VERSION 5.7 ;
  NOWIREEXTENSIONATPIN ON ;
  DIVIDERCHAR "/" ;
  BUSBITCHARS "[]" ;
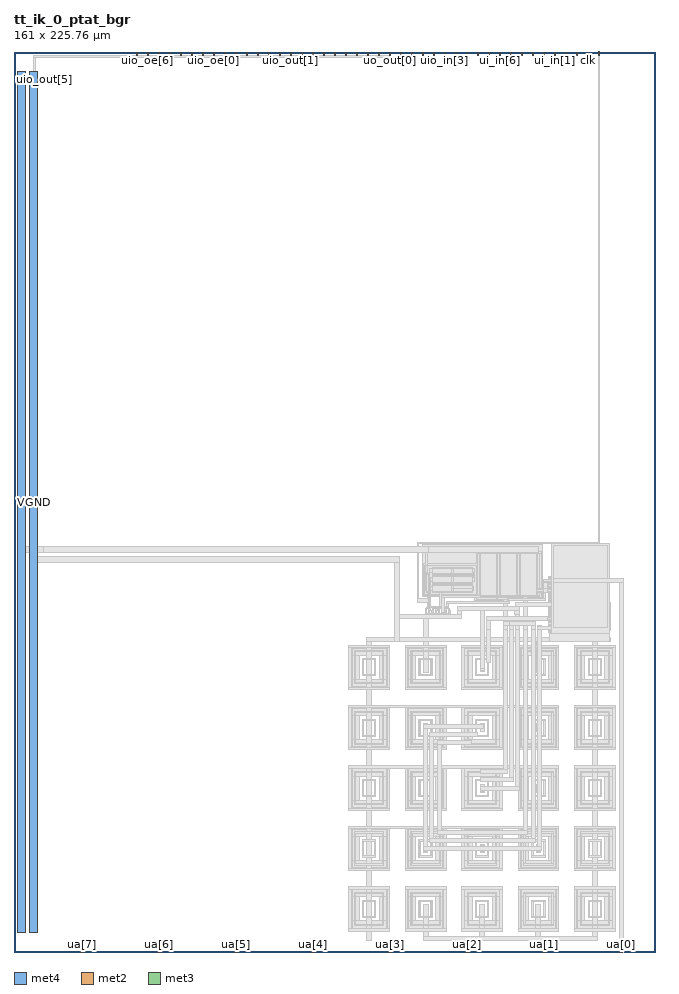
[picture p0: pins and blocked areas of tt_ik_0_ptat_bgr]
MACRO tt_ik_0_ptat_bgr
  CLASS BLOCK ;
  FOREIGN tt_ik_0_ptat_bgr ;
  ORIGIN 0.000 0.000 ;
  SIZE 161.000 BY 225.760 ;
  PIN clk
    DIRECTION INPUT ;
    USE SIGNAL ;
    PORT
      LAYER met4 ;
        RECT 143.830 224.760 144.130 225.760 ;
    END
  END clk
  PIN ena
    DIRECTION INPUT ;
    USE SIGNAL ;
    ANTENNAGATEAREA 1.000000 ;
    PORT
      LAYER met2 ;
        RECT 146.500 225.760 146.950 225.800 ;
      LAYER met3 ;
        RECT 146.500 225.760 146.950 225.800 ;
      LAYER met4 ;
        RECT 146.500 225.760 146.950 225.800 ;
        RECT 146.590 224.760 146.890 225.760 ;
    END
  END ena
  PIN rst_n
    DIRECTION INPUT ;
    USE SIGNAL ;
    PORT
      LAYER met4 ;
        RECT 141.070 224.760 141.370 225.760 ;
    END
  END rst_n
  PIN ua[0]
    DIRECTION INOUT ;
    USE SIGNAL ;
    PORT
      LAYER met4 ;
        RECT 151.810 0.000 152.710 1.000 ;
    END
  END ua[0]
  PIN ua[1]
    DIRECTION INOUT ;
    USE SIGNAL ;
    PORT
      LAYER met4 ;
        RECT 132.490 0.000 133.390 1.000 ;
    END
  END ua[1]
  PIN ua[2]
    DIRECTION INOUT ;
    USE SIGNAL ;
    PORT
      LAYER met4 ;
        RECT 113.170 0.000 114.070 1.000 ;
    END
  END ua[2]
  PIN ua[3]
    DIRECTION INOUT ;
    USE SIGNAL ;
    PORT
      LAYER met4 ;
        RECT 93.850 0.000 94.750 1.000 ;
    END
  END ua[3]
  PIN ua[4]
    DIRECTION INOUT ;
    USE SIGNAL ;
    PORT
      LAYER met4 ;
        RECT 74.530 0.000 75.430 1.000 ;
    END
  END ua[4]
  PIN ua[5]
    DIRECTION INOUT ;
    USE SIGNAL ;
    PORT
      LAYER met4 ;
        RECT 55.210 0.000 56.110 1.000 ;
    END
  END ua[5]
  PIN ua[6]
    DIRECTION INOUT ;
    USE SIGNAL ;
    PORT
      LAYER met4 ;
        RECT 35.890 0.000 36.790 1.000 ;
    END
  END ua[6]
  PIN ua[7]
    DIRECTION INOUT ;
    USE SIGNAL ;
    PORT
      LAYER met4 ;
        RECT 16.570 0.000 17.470 1.000 ;
    END
  END ua[7]
  PIN ui_in[0]
    DIRECTION INPUT ;
    USE SIGNAL ;
    PORT
      LAYER met4 ;
        RECT 138.310 224.760 138.610 225.760 ;
    END
  END ui_in[0]
  PIN ui_in[1]
    DIRECTION INPUT ;
    USE SIGNAL ;
    PORT
      LAYER met4 ;
        RECT 135.550 224.760 135.850 225.760 ;
    END
  END ui_in[1]
  PIN ui_in[2]
    DIRECTION INPUT ;
    USE SIGNAL ;
    PORT
      LAYER met4 ;
        RECT 132.790 224.760 133.090 225.760 ;
    END
  END ui_in[2]
  PIN ui_in[3]
    DIRECTION INPUT ;
    USE SIGNAL ;
    PORT
      LAYER met4 ;
        RECT 130.030 224.760 130.330 225.760 ;
    END
  END ui_in[3]
  PIN ui_in[4]
    DIRECTION INPUT ;
    USE SIGNAL ;
    PORT
      LAYER met4 ;
        RECT 127.270 224.760 127.570 225.760 ;
    END
  END ui_in[4]
  PIN ui_in[5]
    DIRECTION INPUT ;
    USE SIGNAL ;
    PORT
      LAYER met4 ;
        RECT 124.510 224.760 124.810 225.760 ;
    END
  END ui_in[5]
  PIN ui_in[6]
    DIRECTION INPUT ;
    USE SIGNAL ;
    PORT
      LAYER met4 ;
        RECT 121.750 224.760 122.050 225.760 ;
    END
  END ui_in[6]
  PIN ui_in[7]
    DIRECTION INPUT ;
    USE SIGNAL ;
    PORT
      LAYER met4 ;
        RECT 118.990 224.760 119.290 225.760 ;
    END
  END ui_in[7]
  PIN uio_in[0]
    DIRECTION INPUT ;
    USE SIGNAL ;
    PORT
      LAYER met4 ;
        RECT 116.230 224.760 116.530 225.760 ;
    END
  END uio_in[0]
  PIN uio_in[1]
    DIRECTION INPUT ;
    USE SIGNAL ;
    PORT
      LAYER met4 ;
        RECT 113.470 224.760 113.770 225.760 ;
    END
  END uio_in[1]
  PIN uio_in[2]
    DIRECTION INPUT ;
    USE SIGNAL ;
    PORT
      LAYER met4 ;
        RECT 110.710 224.760 111.010 225.760 ;
    END
  END uio_in[2]
  PIN uio_in[3]
    DIRECTION INPUT ;
    USE SIGNAL ;
    PORT
      LAYER met4 ;
        RECT 107.950 224.760 108.250 225.760 ;
    END
  END uio_in[3]
  PIN uio_in[4]
    DIRECTION INPUT ;
    USE SIGNAL ;
    PORT
      LAYER met4 ;
        RECT 105.190 224.760 105.490 225.760 ;
    END
  END uio_in[4]
  PIN uio_in[5]
    DIRECTION INPUT ;
    USE SIGNAL ;
    PORT
      LAYER met4 ;
        RECT 102.430 224.760 102.730 225.760 ;
    END
  END uio_in[5]
  PIN uio_in[6]
    DIRECTION INPUT ;
    USE SIGNAL ;
    PORT
      LAYER met4 ;
        RECT 99.670 224.760 99.970 225.760 ;
    END
  END uio_in[6]
  PIN uio_in[7]
    DIRECTION INPUT ;
    USE SIGNAL ;
    PORT
      LAYER met4 ;
        RECT 96.910 224.760 97.210 225.760 ;
    END
  END uio_in[7]
  PIN uio_oe[0]
    DIRECTION OUTPUT ;
    USE SIGNAL ;
    ANTENNAGATEAREA 453.306000 ;
    ANTENNADIFFAREA 915.978760 ;
    PORT
      LAYER met4 ;
        RECT 49.990 224.760 50.290 225.760 ;
    END
  END uio_oe[0]
  PIN uio_oe[1]
    DIRECTION OUTPUT ;
    USE SIGNAL ;
    ANTENNAGATEAREA 453.306000 ;
    ANTENNADIFFAREA 915.978760 ;
    PORT
      LAYER met4 ;
        RECT 47.230 224.760 47.530 225.760 ;
    END
  END uio_oe[1]
  PIN uio_oe[2]
    DIRECTION OUTPUT ;
    USE SIGNAL ;
    ANTENNAGATEAREA 453.306000 ;
    ANTENNADIFFAREA 915.978760 ;
    PORT
      LAYER met4 ;
        RECT 44.470 224.760 44.770 225.760 ;
    END
  END uio_oe[2]
  PIN uio_oe[3]
    DIRECTION OUTPUT ;
    USE SIGNAL ;
    ANTENNAGATEAREA 453.306000 ;
    ANTENNADIFFAREA 915.978760 ;
    PORT
      LAYER met4 ;
        RECT 41.710 224.760 42.010 225.760 ;
    END
  END uio_oe[3]
  PIN uio_oe[4]
    DIRECTION OUTPUT ;
    USE SIGNAL ;
    ANTENNAGATEAREA 453.306000 ;
    ANTENNADIFFAREA 915.978760 ;
    PORT
      LAYER met4 ;
        RECT 38.950 224.760 39.250 225.760 ;
    END
  END uio_oe[4]
  PIN uio_oe[5]
    DIRECTION OUTPUT ;
    USE SIGNAL ;
    ANTENNAGATEAREA 453.306000 ;
    ANTENNADIFFAREA 915.978760 ;
    PORT
      LAYER met4 ;
        RECT 36.190 224.760 36.490 225.760 ;
    END
  END uio_oe[5]
  PIN uio_oe[6]
    DIRECTION OUTPUT ;
    USE SIGNAL ;
    ANTENNAGATEAREA 453.306000 ;
    ANTENNADIFFAREA 915.978760 ;
    PORT
      LAYER met4 ;
        RECT 33.430 224.760 33.730 225.760 ;
    END
  END uio_oe[6]
  PIN uio_oe[7]
    DIRECTION OUTPUT ;
    USE SIGNAL ;
    ANTENNAGATEAREA 453.306000 ;
    ANTENNADIFFAREA 915.978760 ;
    PORT
      LAYER met4 ;
        RECT 30.670 224.760 30.970 225.760 ;
    END
  END uio_oe[7]
  PIN uo_out[0]
    DIRECTION OUTPUT ;
    USE SIGNAL ;
    ANTENNAGATEAREA 453.306000 ;
    ANTENNADIFFAREA 915.978760 ;
    PORT
      LAYER met4 ;
        RECT 94.150 224.760 94.450 225.760 ;
    END
  END uo_out[0]
  PIN uo_out[1]
    DIRECTION OUTPUT ;
    USE SIGNAL ;
    ANTENNAGATEAREA 453.306000 ;
    ANTENNADIFFAREA 915.978760 ;
    PORT
      LAYER met4 ;
        RECT 91.390 224.760 91.690 225.760 ;
    END
  END uo_out[1]
  PIN uo_out[2]
    DIRECTION OUTPUT ;
    USE SIGNAL ;
    ANTENNAGATEAREA 453.306000 ;
    ANTENNADIFFAREA 915.978760 ;
    PORT
      LAYER met4 ;
        RECT 88.630 224.760 88.930 225.760 ;
    END
  END uo_out[2]
  PIN uo_out[3]
    DIRECTION OUTPUT ;
    USE SIGNAL ;
    ANTENNAGATEAREA 453.306000 ;
    ANTENNADIFFAREA 915.978760 ;
    PORT
      LAYER met4 ;
        RECT 85.870 224.760 86.170 225.760 ;
    END
  END uo_out[3]
  PIN uo_out[4]
    DIRECTION OUTPUT ;
    USE SIGNAL ;
    ANTENNAGATEAREA 453.306000 ;
    ANTENNADIFFAREA 915.978760 ;
    PORT
      LAYER met4 ;
        RECT 83.110 224.760 83.410 225.760 ;
    END
  END uo_out[4]
  PIN uo_out[5]
    DIRECTION OUTPUT ;
    USE SIGNAL ;
    ANTENNAGATEAREA 453.306000 ;
    ANTENNADIFFAREA 915.978760 ;
    PORT
      LAYER met4 ;
        RECT 80.350 224.760 80.650 225.760 ;
    END
  END uo_out[5]
  PIN uo_out[6]
    DIRECTION OUTPUT ;
    USE SIGNAL ;
    ANTENNAGATEAREA 453.306000 ;
    ANTENNADIFFAREA 915.978760 ;
    PORT
      LAYER met4 ;
        RECT 77.590 224.760 77.890 225.760 ;
    END
  END uo_out[6]
  PIN uo_out[7]
    DIRECTION OUTPUT ;
    USE SIGNAL ;
    ANTENNAGATEAREA 453.306000 ;
    ANTENNADIFFAREA 915.978760 ;
    PORT
      LAYER met4 ;
        RECT 74.830 224.760 75.130 225.760 ;
    END
  END uo_out[7]
  PIN VGND
    DIRECTION INOUT ;
    USE GROUND ;
    PORT
      LAYER met4 ;
        RECT 4.000 5.000 6.000 220.760 ;
    END
  END VGND
  PIN uio_out[0]
    DIRECTION OUTPUT ;
    USE SIGNAL ;
    PORT
      LAYER met4 ;
        RECT 72.070 224.760 72.370 225.760 ;
    END
  END uio_out[0]
  PIN uio_out[1]
    DIRECTION OUTPUT ;
    USE SIGNAL ;
    PORT
      LAYER met4 ;
        RECT 69.310 224.760 69.610 225.760 ;
    END
  END uio_out[1]
  PIN uio_out[2]
    DIRECTION OUTPUT ;
    USE SIGNAL ;
    PORT
      LAYER met4 ;
        RECT 66.550 224.760 66.850 225.760 ;
    END
  END uio_out[2]
  PIN uio_out[3]
    DIRECTION OUTPUT ;
    USE SIGNAL ;
    PORT
      LAYER met4 ;
        RECT 63.790 224.760 64.090 225.760 ;
    END
  END uio_out[3]
  PIN uio_out[4]
    DIRECTION OUTPUT ;
    USE SIGNAL ;
    PORT
      LAYER met4 ;
        RECT 61.030 224.760 61.330 225.760 ;
    END
  END uio_out[4]
  PIN uio_out[5]
    DIRECTION OUTPUT ;
    USE SIGNAL ;
    PORT
      LAYER met4 ;
        RECT 58.270 224.760 58.570 225.760 ;
    END
    PORT
      LAYER met4 ;
        RECT 1.000 5.000 3.000 220.760 ;
    END
  END uio_out[5]
  PIN uio_out[6]
    DIRECTION OUTPUT ;
    USE SIGNAL ;
    PORT
      LAYER met4 ;
        RECT 55.510 224.760 55.810 225.760 ;
    END
  END uio_out[6]
  PIN uio_out[7]
    DIRECTION OUTPUT ;
    USE SIGNAL ;
    PORT
      LAYER met4 ;
        RECT 52.750 224.760 53.050 225.760 ;
    END
  END uio_out[7]
  OBS
      LAYER nwell ;
        RECT 102.400 89.100 132.600 102.100 ;
        RECT 115.600 88.100 132.600 89.100 ;
      LAYER pwell ;
        RECT 134.200 80.100 148.200 94.300 ;
      LAYER nwell ;
        RECT 84.800 74.420 93.420 76.220 ;
        RECT 84.800 68.400 86.600 74.420 ;
        RECT 91.620 68.400 93.420 74.420 ;
        RECT 84.800 66.600 93.420 68.400 ;
        RECT 98.950 74.420 107.570 76.220 ;
        RECT 98.950 68.400 100.750 74.420 ;
        RECT 105.770 68.400 107.570 74.420 ;
        RECT 98.950 66.600 107.570 68.400 ;
        RECT 113.100 74.420 121.720 76.220 ;
        RECT 113.100 68.400 114.900 74.420 ;
        RECT 119.920 68.400 121.720 74.420 ;
        RECT 113.100 66.600 121.720 68.400 ;
        RECT 127.250 74.420 135.870 76.220 ;
        RECT 127.250 68.400 129.050 74.420 ;
        RECT 134.070 68.400 135.870 74.420 ;
        RECT 127.250 66.600 135.870 68.400 ;
        RECT 141.400 74.420 150.020 76.220 ;
        RECT 141.400 68.400 143.200 74.420 ;
        RECT 148.220 68.400 150.020 74.420 ;
        RECT 141.400 66.600 150.020 68.400 ;
        RECT 84.800 59.270 93.420 61.070 ;
        RECT 84.800 53.250 86.600 59.270 ;
        RECT 91.620 53.250 93.420 59.270 ;
        RECT 84.800 51.450 93.420 53.250 ;
        RECT 98.950 59.270 107.570 61.070 ;
        RECT 98.950 53.250 100.750 59.270 ;
        RECT 105.770 53.250 107.570 59.270 ;
        RECT 98.950 51.450 107.570 53.250 ;
        RECT 113.100 59.270 121.720 61.070 ;
        RECT 113.100 53.250 114.900 59.270 ;
        RECT 119.920 53.250 121.720 59.270 ;
        RECT 113.100 51.450 121.720 53.250 ;
        RECT 127.250 59.270 135.870 61.070 ;
        RECT 127.250 53.250 129.050 59.270 ;
        RECT 134.070 53.250 135.870 59.270 ;
        RECT 127.250 51.450 135.870 53.250 ;
        RECT 141.400 59.270 150.020 61.070 ;
        RECT 141.400 53.250 143.200 59.270 ;
        RECT 148.220 53.250 150.020 59.270 ;
        RECT 141.400 51.450 150.020 53.250 ;
        RECT 84.800 44.120 93.420 45.920 ;
        RECT 84.800 38.100 86.600 44.120 ;
        RECT 91.620 38.100 93.420 44.120 ;
        RECT 84.800 36.300 93.420 38.100 ;
        RECT 98.950 44.120 107.570 45.920 ;
        RECT 98.950 38.100 100.750 44.120 ;
        RECT 105.770 38.100 107.570 44.120 ;
        RECT 98.950 36.300 107.570 38.100 ;
        RECT 113.100 44.120 121.720 45.920 ;
        RECT 113.100 38.100 114.900 44.120 ;
        RECT 119.920 38.100 121.720 44.120 ;
        RECT 113.100 36.300 121.720 38.100 ;
        RECT 127.250 44.120 135.870 45.920 ;
        RECT 127.250 38.100 129.050 44.120 ;
        RECT 134.070 38.100 135.870 44.120 ;
        RECT 127.250 36.300 135.870 38.100 ;
        RECT 141.400 44.120 150.020 45.920 ;
        RECT 141.400 38.100 143.200 44.120 ;
        RECT 148.220 38.100 150.020 44.120 ;
        RECT 141.400 36.300 150.020 38.100 ;
        RECT 84.800 28.970 93.420 30.770 ;
        RECT 84.800 22.950 86.600 28.970 ;
        RECT 91.620 22.950 93.420 28.970 ;
        RECT 84.800 21.150 93.420 22.950 ;
        RECT 98.950 28.970 107.570 30.770 ;
        RECT 98.950 22.950 100.750 28.970 ;
        RECT 105.770 22.950 107.570 28.970 ;
        RECT 98.950 21.150 107.570 22.950 ;
        RECT 113.100 28.970 121.720 30.770 ;
        RECT 113.100 22.950 114.900 28.970 ;
        RECT 119.920 22.950 121.720 28.970 ;
        RECT 113.100 21.150 121.720 22.950 ;
        RECT 127.250 28.970 135.870 30.770 ;
        RECT 127.250 22.950 129.050 28.970 ;
        RECT 134.070 22.950 135.870 28.970 ;
        RECT 127.250 21.150 135.870 22.950 ;
        RECT 141.400 28.970 150.020 30.770 ;
        RECT 141.400 22.950 143.200 28.970 ;
        RECT 148.220 22.950 150.020 28.970 ;
        RECT 141.400 21.150 150.020 22.950 ;
        RECT 84.800 13.820 93.420 15.620 ;
        RECT 84.800 7.800 86.600 13.820 ;
        RECT 91.620 7.800 93.420 13.820 ;
        RECT 84.800 6.000 93.420 7.800 ;
        RECT 98.950 13.820 107.570 15.620 ;
        RECT 98.950 7.800 100.750 13.820 ;
        RECT 105.770 7.800 107.570 13.820 ;
        RECT 98.950 6.000 107.570 7.800 ;
        RECT 113.100 13.820 121.720 15.620 ;
        RECT 113.100 7.800 114.900 13.820 ;
        RECT 119.920 7.800 121.720 13.820 ;
        RECT 113.100 6.000 121.720 7.800 ;
        RECT 127.250 13.820 135.870 15.620 ;
        RECT 127.250 7.800 129.050 13.820 ;
        RECT 134.070 7.800 135.870 13.820 ;
        RECT 127.250 6.000 135.870 7.800 ;
        RECT 141.400 13.820 150.020 15.620 ;
        RECT 141.400 7.800 143.200 13.820 ;
        RECT 148.220 7.800 150.020 13.820 ;
        RECT 141.400 6.000 150.020 7.800 ;
      LAYER li1 ;
        RECT 115.900 100.000 132.300 100.400 ;
        RECT 115.900 97.400 116.300 100.000 ;
        RECT 102.600 97.000 116.300 97.400 ;
        RECT 102.600 89.800 103.000 97.000 ;
        RECT 105.070 96.335 115.070 96.505 ;
        RECT 103.440 95.080 103.610 96.120 ;
        RECT 104.230 95.080 104.400 96.120 ;
        RECT 104.840 95.080 105.010 96.120 ;
        RECT 115.130 95.080 115.300 96.120 ;
        RECT 103.670 94.695 104.170 94.865 ;
        RECT 105.070 94.695 115.070 94.865 ;
        RECT 105.070 94.135 115.070 94.305 ;
        RECT 104.840 92.880 105.010 93.920 ;
        RECT 115.130 92.880 115.300 93.920 ;
        RECT 105.070 92.495 115.070 92.665 ;
        RECT 105.070 91.935 115.070 92.105 ;
        RECT 103.340 90.680 103.510 91.720 ;
        RECT 104.130 90.680 104.300 91.720 ;
        RECT 104.840 90.680 105.010 91.720 ;
        RECT 115.130 90.680 115.300 91.720 ;
        RECT 103.570 90.295 104.070 90.465 ;
        RECT 105.070 90.295 115.070 90.465 ;
        RECT 115.900 89.800 116.300 97.000 ;
        RECT 102.600 89.400 116.300 89.800 ;
        RECT 116.840 89.580 117.010 99.620 ;
        RECT 121.130 89.580 121.300 99.620 ;
        RECT 121.840 89.580 122.010 99.620 ;
        RECT 126.130 89.580 126.300 99.620 ;
        RECT 126.840 89.580 127.010 99.620 ;
        RECT 131.130 89.580 131.300 99.620 ;
        RECT 115.900 88.800 116.300 89.400 ;
        RECT 117.070 89.195 121.070 89.365 ;
        RECT 122.070 89.195 126.070 89.365 ;
        RECT 127.070 89.195 131.070 89.365 ;
        RECT 131.900 88.800 132.300 100.000 ;
        RECT 134.380 93.950 147.840 94.120 ;
        RECT 134.380 92.300 134.550 93.950 ;
        RECT 135.030 92.780 137.190 93.470 ;
        RECT 145.030 92.780 147.190 93.470 ;
        RECT 147.670 92.300 147.840 93.950 ;
        RECT 134.380 92.130 147.840 92.300 ;
        RECT 140.900 91.800 141.900 92.130 ;
        RECT 115.900 88.400 132.300 88.800 ;
        RECT 134.400 91.600 148.000 91.800 ;
        RECT 134.400 87.600 134.600 91.600 ;
        RECT 135.140 90.310 137.300 91.000 ;
        RECT 145.140 90.310 147.300 91.000 ;
        RECT 135.140 89.310 137.300 90.000 ;
        RECT 145.140 89.310 147.300 90.000 ;
        RECT 135.140 88.310 137.300 89.000 ;
        RECT 145.140 88.310 147.300 89.000 ;
        RECT 134.000 86.800 134.600 87.600 ;
        RECT 135.140 87.310 137.300 88.000 ;
        RECT 145.140 87.310 147.300 88.000 ;
        RECT 103.540 86.320 104.040 86.490 ;
        RECT 105.190 86.320 105.690 86.490 ;
        RECT 106.840 86.320 107.340 86.490 ;
        RECT 108.490 86.320 108.990 86.490 ;
        RECT 103.310 85.110 103.480 86.150 ;
        RECT 104.100 85.110 104.270 86.150 ;
        RECT 104.960 85.110 105.130 86.150 ;
        RECT 105.750 85.110 105.920 86.150 ;
        RECT 106.610 85.110 106.780 86.150 ;
        RECT 107.400 85.110 107.570 86.150 ;
        RECT 108.260 85.110 108.430 86.150 ;
        RECT 109.050 85.110 109.220 86.150 ;
        RECT 125.600 84.600 126.600 85.600 ;
        RECT 134.400 82.800 134.600 86.800 ;
        RECT 135.140 86.310 137.300 87.000 ;
        RECT 145.140 86.310 147.300 87.000 ;
        RECT 135.140 85.310 137.300 86.000 ;
        RECT 145.140 85.310 147.300 86.000 ;
        RECT 135.140 84.310 137.300 85.000 ;
        RECT 145.140 84.310 147.300 85.000 ;
        RECT 135.140 83.310 137.300 84.000 ;
        RECT 145.140 83.310 147.300 84.000 ;
        RECT 147.800 82.800 148.000 91.600 ;
        RECT 134.400 82.600 148.000 82.800 ;
        RECT 140.900 82.270 141.900 82.600 ;
        RECT 134.380 82.100 147.840 82.270 ;
        RECT 134.380 80.450 134.550 82.100 ;
        RECT 135.030 80.930 137.190 81.620 ;
        RECT 145.030 80.930 147.190 81.620 ;
        RECT 147.670 80.450 147.840 82.100 ;
        RECT 134.380 80.280 147.840 80.450 ;
        RECT 145.200 78.850 146.200 80.280 ;
        RECT 84.000 76.400 94.200 77.000 ;
        RECT 84.000 66.400 84.600 76.400 ;
        RECT 85.430 75.260 92.790 75.590 ;
        RECT 85.430 67.560 85.760 75.260 ;
        RECT 87.440 73.250 90.780 73.580 ;
        RECT 87.440 69.570 87.770 73.250 ;
        RECT 88.605 70.395 89.615 72.425 ;
        RECT 90.450 69.570 90.780 73.250 ;
        RECT 87.440 69.240 90.780 69.570 ;
        RECT 92.460 67.560 92.790 75.260 ;
        RECT 85.430 67.230 92.790 67.560 ;
        RECT 93.600 66.400 94.200 76.400 ;
        RECT 84.000 65.800 94.200 66.400 ;
        RECT 98.200 76.400 108.400 77.000 ;
        RECT 98.200 66.400 98.800 76.400 ;
        RECT 99.580 75.260 106.940 75.590 ;
        RECT 99.580 67.560 99.910 75.260 ;
        RECT 101.590 73.250 104.930 73.580 ;
        RECT 101.590 69.570 101.920 73.250 ;
        RECT 102.755 70.395 103.765 72.425 ;
        RECT 104.600 69.570 104.930 73.250 ;
        RECT 101.590 69.240 104.930 69.570 ;
        RECT 106.610 67.560 106.940 75.260 ;
        RECT 99.580 67.230 106.940 67.560 ;
        RECT 107.800 66.400 108.400 76.400 ;
        RECT 98.200 65.800 108.400 66.400 ;
        RECT 112.300 76.400 122.500 77.000 ;
        RECT 112.300 66.400 112.900 76.400 ;
        RECT 113.730 75.260 121.090 75.590 ;
        RECT 113.730 67.560 114.060 75.260 ;
        RECT 115.740 73.250 119.080 73.580 ;
        RECT 115.740 69.570 116.070 73.250 ;
        RECT 116.905 70.395 117.915 72.425 ;
        RECT 118.750 69.570 119.080 73.250 ;
        RECT 115.740 69.240 119.080 69.570 ;
        RECT 120.760 67.560 121.090 75.260 ;
        RECT 113.730 67.230 121.090 67.560 ;
        RECT 121.900 66.400 122.500 76.400 ;
        RECT 112.300 65.800 122.500 66.400 ;
        RECT 126.500 76.400 136.700 77.000 ;
        RECT 126.500 66.400 127.100 76.400 ;
        RECT 127.880 75.260 135.240 75.590 ;
        RECT 127.880 67.560 128.210 75.260 ;
        RECT 129.890 73.250 133.230 73.580 ;
        RECT 129.890 69.570 130.220 73.250 ;
        RECT 131.055 70.395 132.065 72.425 ;
        RECT 132.900 69.570 133.230 73.250 ;
        RECT 129.890 69.240 133.230 69.570 ;
        RECT 134.910 67.560 135.240 75.260 ;
        RECT 127.880 67.230 135.240 67.560 ;
        RECT 136.100 66.400 136.700 76.400 ;
        RECT 126.500 65.800 136.700 66.400 ;
        RECT 140.600 76.400 150.800 77.000 ;
        RECT 140.600 66.400 141.200 76.400 ;
        RECT 142.030 75.260 149.390 75.590 ;
        RECT 142.030 67.560 142.360 75.260 ;
        RECT 144.040 73.250 147.380 73.580 ;
        RECT 144.040 69.570 144.370 73.250 ;
        RECT 145.205 70.395 146.215 72.425 ;
        RECT 147.050 69.570 147.380 73.250 ;
        RECT 144.040 69.240 147.380 69.570 ;
        RECT 149.060 67.560 149.390 75.260 ;
        RECT 142.030 67.230 149.390 67.560 ;
        RECT 150.200 66.400 150.800 76.400 ;
        RECT 140.600 65.800 150.800 66.400 ;
        RECT 84.000 61.300 94.200 61.900 ;
        RECT 84.000 51.300 84.600 61.300 ;
        RECT 85.430 60.110 92.790 60.440 ;
        RECT 85.430 52.410 85.760 60.110 ;
        RECT 87.440 58.100 90.780 58.430 ;
        RECT 87.440 54.420 87.770 58.100 ;
        RECT 88.605 55.245 89.615 57.275 ;
        RECT 90.450 54.420 90.780 58.100 ;
        RECT 87.440 54.090 90.780 54.420 ;
        RECT 92.460 52.410 92.790 60.110 ;
        RECT 85.430 52.080 92.790 52.410 ;
        RECT 93.600 51.300 94.200 61.300 ;
        RECT 84.000 50.700 94.200 51.300 ;
        RECT 98.200 61.300 108.400 61.900 ;
        RECT 98.200 51.300 98.800 61.300 ;
        RECT 99.580 60.110 106.940 60.440 ;
        RECT 99.580 52.410 99.910 60.110 ;
        RECT 101.590 58.100 104.930 58.430 ;
        RECT 101.590 54.420 101.920 58.100 ;
        RECT 102.755 55.245 103.765 57.275 ;
        RECT 104.600 54.420 104.930 58.100 ;
        RECT 101.590 54.090 104.930 54.420 ;
        RECT 106.610 52.410 106.940 60.110 ;
        RECT 99.580 52.080 106.940 52.410 ;
        RECT 107.800 51.300 108.400 61.300 ;
        RECT 98.200 50.700 108.400 51.300 ;
        RECT 112.300 61.300 122.500 61.900 ;
        RECT 112.300 51.300 112.900 61.300 ;
        RECT 113.730 60.110 121.090 60.440 ;
        RECT 113.730 52.410 114.060 60.110 ;
        RECT 115.740 58.100 119.080 58.430 ;
        RECT 115.740 54.420 116.070 58.100 ;
        RECT 116.905 55.245 117.915 57.275 ;
        RECT 118.750 54.420 119.080 58.100 ;
        RECT 115.740 54.090 119.080 54.420 ;
        RECT 120.760 52.410 121.090 60.110 ;
        RECT 113.730 52.080 121.090 52.410 ;
        RECT 121.900 51.300 122.500 61.300 ;
        RECT 112.300 50.700 122.500 51.300 ;
        RECT 126.500 61.300 136.700 61.900 ;
        RECT 126.500 51.300 127.100 61.300 ;
        RECT 127.880 60.110 135.240 60.440 ;
        RECT 127.880 52.410 128.210 60.110 ;
        RECT 129.890 58.100 133.230 58.430 ;
        RECT 129.890 54.420 130.220 58.100 ;
        RECT 131.055 55.245 132.065 57.275 ;
        RECT 132.900 54.420 133.230 58.100 ;
        RECT 129.890 54.090 133.230 54.420 ;
        RECT 134.910 52.410 135.240 60.110 ;
        RECT 127.880 52.080 135.240 52.410 ;
        RECT 136.100 51.300 136.700 61.300 ;
        RECT 126.500 50.700 136.700 51.300 ;
        RECT 140.600 61.300 150.800 61.900 ;
        RECT 140.600 51.300 141.200 61.300 ;
        RECT 142.030 60.110 149.390 60.440 ;
        RECT 142.030 52.410 142.360 60.110 ;
        RECT 144.040 58.100 147.380 58.430 ;
        RECT 144.040 54.420 144.370 58.100 ;
        RECT 145.205 55.245 146.215 57.275 ;
        RECT 147.050 54.420 147.380 58.100 ;
        RECT 144.040 54.090 147.380 54.420 ;
        RECT 149.060 52.410 149.390 60.110 ;
        RECT 142.030 52.080 149.390 52.410 ;
        RECT 150.200 51.300 150.800 61.300 ;
        RECT 140.600 50.700 150.800 51.300 ;
        RECT 84.000 46.100 94.200 46.700 ;
        RECT 84.000 36.100 84.600 46.100 ;
        RECT 85.430 44.960 92.790 45.290 ;
        RECT 85.430 37.260 85.760 44.960 ;
        RECT 87.440 42.950 90.780 43.280 ;
        RECT 87.440 39.270 87.770 42.950 ;
        RECT 88.605 40.095 89.615 42.125 ;
        RECT 90.450 39.270 90.780 42.950 ;
        RECT 87.440 38.940 90.780 39.270 ;
        RECT 92.460 37.260 92.790 44.960 ;
        RECT 85.430 36.930 92.790 37.260 ;
        RECT 93.600 36.100 94.200 46.100 ;
        RECT 84.000 35.500 94.200 36.100 ;
        RECT 98.200 46.100 108.400 46.700 ;
        RECT 98.200 36.100 98.800 46.100 ;
        RECT 99.580 44.960 106.940 45.290 ;
        RECT 99.580 37.260 99.910 44.960 ;
        RECT 101.590 42.950 104.930 43.280 ;
        RECT 101.590 39.270 101.920 42.950 ;
        RECT 102.755 40.095 103.765 42.125 ;
        RECT 104.600 39.270 104.930 42.950 ;
        RECT 101.590 38.940 104.930 39.270 ;
        RECT 106.610 37.260 106.940 44.960 ;
        RECT 99.580 36.930 106.940 37.260 ;
        RECT 107.800 36.100 108.400 46.100 ;
        RECT 98.200 35.500 108.400 36.100 ;
        RECT 112.300 46.100 122.500 46.700 ;
        RECT 112.300 36.100 112.900 46.100 ;
        RECT 113.730 44.960 121.090 45.290 ;
        RECT 113.730 37.260 114.060 44.960 ;
        RECT 115.740 42.950 119.080 43.280 ;
        RECT 115.740 39.270 116.070 42.950 ;
        RECT 116.905 40.095 117.915 42.125 ;
        RECT 118.750 39.270 119.080 42.950 ;
        RECT 115.740 38.940 119.080 39.270 ;
        RECT 120.760 37.260 121.090 44.960 ;
        RECT 113.730 36.930 121.090 37.260 ;
        RECT 121.900 36.100 122.500 46.100 ;
        RECT 112.300 35.500 122.500 36.100 ;
        RECT 126.500 46.100 136.700 46.700 ;
        RECT 126.500 36.100 127.100 46.100 ;
        RECT 127.880 44.960 135.240 45.290 ;
        RECT 127.880 37.260 128.210 44.960 ;
        RECT 129.890 42.950 133.230 43.280 ;
        RECT 129.890 39.270 130.220 42.950 ;
        RECT 131.055 40.095 132.065 42.125 ;
        RECT 132.900 39.270 133.230 42.950 ;
        RECT 129.890 38.940 133.230 39.270 ;
        RECT 134.910 37.260 135.240 44.960 ;
        RECT 127.880 36.930 135.240 37.260 ;
        RECT 136.100 36.100 136.700 46.100 ;
        RECT 126.500 35.500 136.700 36.100 ;
        RECT 140.600 46.100 150.800 46.700 ;
        RECT 140.600 36.100 141.200 46.100 ;
        RECT 142.030 44.960 149.390 45.290 ;
        RECT 142.030 37.260 142.360 44.960 ;
        RECT 144.040 42.950 147.380 43.280 ;
        RECT 144.040 39.270 144.370 42.950 ;
        RECT 145.205 40.095 146.215 42.125 ;
        RECT 147.050 39.270 147.380 42.950 ;
        RECT 144.040 38.940 147.380 39.270 ;
        RECT 149.060 37.260 149.390 44.960 ;
        RECT 142.030 36.930 149.390 37.260 ;
        RECT 150.200 36.100 150.800 46.100 ;
        RECT 140.600 35.500 150.800 36.100 ;
        RECT 84.000 31.000 136.700 31.600 ;
        RECT 84.000 21.000 84.600 31.000 ;
        RECT 85.430 29.810 92.790 30.140 ;
        RECT 85.430 22.110 85.760 29.810 ;
        RECT 87.440 27.800 90.780 28.130 ;
        RECT 87.440 24.120 87.770 27.800 ;
        RECT 88.605 24.945 89.615 26.975 ;
        RECT 90.450 24.120 90.780 27.800 ;
        RECT 87.440 23.790 90.780 24.120 ;
        RECT 92.460 22.110 92.790 29.810 ;
        RECT 85.430 21.780 92.790 22.110 ;
        RECT 93.600 21.000 94.200 31.000 ;
        RECT 84.000 20.400 94.200 21.000 ;
        RECT 98.200 21.000 98.800 31.000 ;
        RECT 99.580 29.810 106.940 30.140 ;
        RECT 99.580 22.110 99.910 29.810 ;
        RECT 101.590 27.800 104.930 28.130 ;
        RECT 101.590 24.120 101.920 27.800 ;
        RECT 102.755 24.945 103.765 26.975 ;
        RECT 104.600 24.120 104.930 27.800 ;
        RECT 101.590 23.790 104.930 24.120 ;
        RECT 106.610 22.110 106.940 29.810 ;
        RECT 99.580 21.780 106.940 22.110 ;
        RECT 107.800 21.000 108.400 31.000 ;
        RECT 98.200 20.400 108.400 21.000 ;
        RECT 112.300 21.000 112.900 31.000 ;
        RECT 113.730 29.810 121.090 30.140 ;
        RECT 113.730 22.110 114.060 29.810 ;
        RECT 115.740 27.800 119.080 28.130 ;
        RECT 115.740 24.120 116.070 27.800 ;
        RECT 116.905 24.945 117.915 26.975 ;
        RECT 118.750 24.120 119.080 27.800 ;
        RECT 115.740 23.790 119.080 24.120 ;
        RECT 120.760 22.110 121.090 29.810 ;
        RECT 113.730 21.780 121.090 22.110 ;
        RECT 121.900 21.000 122.500 31.000 ;
        RECT 112.300 20.400 122.500 21.000 ;
        RECT 126.500 21.000 127.100 31.000 ;
        RECT 127.880 29.810 135.240 30.140 ;
        RECT 127.880 22.110 128.210 29.810 ;
        RECT 129.890 27.800 133.230 28.130 ;
        RECT 129.890 24.120 130.220 27.800 ;
        RECT 131.055 24.945 132.065 26.975 ;
        RECT 132.900 24.120 133.230 27.800 ;
        RECT 129.890 23.790 133.230 24.120 ;
        RECT 134.910 22.110 135.240 29.810 ;
        RECT 127.880 21.780 135.240 22.110 ;
        RECT 136.100 21.000 136.700 31.000 ;
        RECT 126.500 20.400 136.700 21.000 ;
        RECT 140.600 31.000 150.800 31.600 ;
        RECT 140.600 21.000 141.200 31.000 ;
        RECT 142.030 29.810 149.390 30.140 ;
        RECT 142.030 22.110 142.360 29.810 ;
        RECT 144.040 27.800 147.380 28.130 ;
        RECT 144.040 24.120 144.370 27.800 ;
        RECT 145.205 24.945 146.215 26.975 ;
        RECT 147.050 24.120 147.380 27.800 ;
        RECT 144.040 23.790 147.380 24.120 ;
        RECT 149.060 22.110 149.390 29.810 ;
        RECT 142.030 21.780 149.390 22.110 ;
        RECT 150.200 21.000 150.800 31.000 ;
        RECT 140.600 20.400 150.800 21.000 ;
        RECT 84.000 15.800 94.200 16.400 ;
        RECT 84.000 5.800 84.600 15.800 ;
        RECT 85.430 14.660 92.790 14.990 ;
        RECT 85.430 6.960 85.760 14.660 ;
        RECT 87.440 12.650 90.780 12.980 ;
        RECT 87.440 8.970 87.770 12.650 ;
        RECT 88.605 9.795 89.615 11.825 ;
        RECT 90.450 8.970 90.780 12.650 ;
        RECT 87.440 8.640 90.780 8.970 ;
        RECT 92.460 6.960 92.790 14.660 ;
        RECT 85.430 6.630 92.790 6.960 ;
        RECT 93.600 5.800 94.200 15.800 ;
        RECT 84.000 5.200 94.200 5.800 ;
        RECT 98.200 15.800 108.400 16.400 ;
        RECT 98.200 5.800 98.800 15.800 ;
        RECT 99.580 14.660 106.940 14.990 ;
        RECT 99.580 6.960 99.910 14.660 ;
        RECT 101.590 12.650 104.930 12.980 ;
        RECT 101.590 8.970 101.920 12.650 ;
        RECT 102.755 9.795 103.765 11.825 ;
        RECT 104.600 8.970 104.930 12.650 ;
        RECT 101.590 8.640 104.930 8.970 ;
        RECT 106.610 6.960 106.940 14.660 ;
        RECT 99.580 6.630 106.940 6.960 ;
        RECT 107.800 5.800 108.400 15.800 ;
        RECT 98.200 5.200 108.400 5.800 ;
        RECT 112.300 15.800 122.500 16.400 ;
        RECT 112.300 5.800 112.900 15.800 ;
        RECT 113.730 14.660 121.090 14.990 ;
        RECT 113.730 6.960 114.060 14.660 ;
        RECT 115.740 12.650 119.080 12.980 ;
        RECT 115.740 8.970 116.070 12.650 ;
        RECT 116.905 9.795 117.915 11.825 ;
        RECT 118.750 8.970 119.080 12.650 ;
        RECT 115.740 8.640 119.080 8.970 ;
        RECT 120.760 6.960 121.090 14.660 ;
        RECT 113.730 6.630 121.090 6.960 ;
        RECT 121.900 5.800 122.500 15.800 ;
        RECT 112.300 5.200 122.500 5.800 ;
        RECT 126.500 15.800 136.700 16.400 ;
        RECT 126.500 5.800 127.100 15.800 ;
        RECT 127.880 14.660 135.240 14.990 ;
        RECT 127.880 6.960 128.210 14.660 ;
        RECT 129.890 12.650 133.230 12.980 ;
        RECT 129.890 8.970 130.220 12.650 ;
        RECT 131.055 9.795 132.065 11.825 ;
        RECT 132.900 8.970 133.230 12.650 ;
        RECT 129.890 8.640 133.230 8.970 ;
        RECT 134.910 6.960 135.240 14.660 ;
        RECT 127.880 6.630 135.240 6.960 ;
        RECT 136.100 5.800 136.700 15.800 ;
        RECT 126.500 5.200 136.700 5.800 ;
        RECT 140.600 15.800 150.800 16.400 ;
        RECT 140.600 5.800 141.200 15.800 ;
        RECT 142.030 14.660 149.390 14.990 ;
        RECT 142.030 6.960 142.360 14.660 ;
        RECT 144.040 12.650 147.380 12.980 ;
        RECT 144.040 8.970 144.370 12.650 ;
        RECT 145.205 9.795 146.215 11.825 ;
        RECT 147.050 8.970 147.380 12.650 ;
        RECT 144.040 8.640 147.380 8.970 ;
        RECT 149.060 6.960 149.390 14.660 ;
        RECT 142.030 6.630 149.390 6.960 ;
        RECT 150.200 5.800 150.800 15.800 ;
        RECT 140.600 5.200 150.800 5.800 ;
        RECT 88.500 3.000 89.700 4.100 ;
      LAYER met1 ;
        RECT 101.150 102.350 146.950 102.800 ;
        RECT 101.150 88.700 101.500 102.350 ;
        RECT 102.400 100.100 131.600 101.600 ;
        RECT 103.200 96.900 103.750 100.100 ;
        RECT 116.600 100.000 131.600 100.100 ;
        RECT 103.300 95.100 103.650 96.900 ;
        RECT 105.090 96.305 115.050 96.535 ;
        RECT 104.200 95.100 105.040 96.100 ;
        RECT 103.300 91.700 103.500 95.100 ;
        RECT 109.800 94.895 110.300 96.305 ;
        RECT 115.100 95.100 115.600 96.100 ;
        RECT 103.690 94.850 104.150 94.895 ;
        RECT 103.690 94.665 104.350 94.850 ;
        RECT 105.090 94.665 115.050 94.895 ;
        RECT 103.300 91.650 103.540 91.700 ;
        RECT 103.310 90.700 103.540 91.650 ;
        RECT 104.100 91.400 104.350 94.665 ;
        RECT 109.800 94.335 110.300 94.665 ;
        RECT 105.090 94.105 115.050 94.335 ;
        RECT 104.600 92.900 105.040 93.900 ;
        RECT 104.600 91.700 104.900 92.900 ;
        RECT 109.800 92.695 110.300 94.105 ;
        RECT 115.300 93.900 115.600 95.100 ;
        RECT 115.100 92.900 115.600 93.900 ;
        RECT 105.090 92.465 115.050 92.695 ;
        RECT 109.800 92.135 110.300 92.465 ;
        RECT 105.090 91.905 115.050 92.135 ;
        RECT 104.100 91.000 104.330 91.400 ;
        RECT 104.100 90.700 104.450 91.000 ;
        RECT 104.600 90.700 105.040 91.700 ;
        RECT 109.800 91.300 110.300 91.905 ;
        RECT 115.100 91.300 115.330 91.700 ;
        RECT 109.800 91.100 115.330 91.300 ;
        RECT 103.590 90.265 104.050 90.495 ;
        RECT 103.600 88.700 103.850 90.265 ;
        RECT 101.150 87.700 103.850 88.700 ;
        RECT 103.600 86.520 103.850 87.700 ;
        RECT 104.250 86.550 104.450 90.700 ;
        RECT 109.800 90.495 110.300 91.100 ;
        RECT 115.100 90.700 115.330 91.100 ;
        RECT 105.090 90.265 115.050 90.495 ;
        RECT 106.810 86.550 107.290 90.265 ;
        RECT 116.700 89.550 117.100 100.000 ;
        RECT 121.000 89.550 121.400 99.650 ;
        RECT 121.700 89.550 122.100 100.000 ;
        RECT 126.000 89.400 126.400 99.650 ;
        RECT 126.700 89.550 127.100 100.000 ;
        RECT 131.000 91.300 131.400 99.650 ;
        RECT 132.800 93.420 135.150 93.500 ;
        RECT 147.000 93.420 152.000 93.600 ;
        RECT 132.800 92.830 137.165 93.420 ;
        RECT 145.055 92.830 152.000 93.420 ;
        RECT 132.800 92.750 135.150 92.830 ;
        RECT 132.800 91.300 133.800 92.750 ;
        RECT 147.000 92.600 152.000 92.830 ;
        RECT 131.000 90.950 135.200 91.300 ;
        RECT 131.000 90.360 137.275 90.950 ;
        RECT 145.165 90.360 147.270 90.950 ;
        RECT 131.000 90.300 135.200 90.360 ;
        RECT 131.000 89.550 131.400 90.300 ;
        RECT 146.000 89.950 147.000 90.360 ;
        RECT 116.350 89.100 131.600 89.400 ;
        RECT 135.170 89.360 137.275 89.950 ;
        RECT 145.165 89.360 147.270 89.950 ;
        RECT 116.350 88.850 116.950 89.100 ;
        RECT 121.000 88.300 123.800 88.950 ;
        RECT 104.250 86.520 105.650 86.550 ;
        RECT 103.560 86.290 104.020 86.520 ;
        RECT 104.250 86.300 105.670 86.520 ;
        RECT 104.250 86.130 104.450 86.300 ;
        RECT 105.210 86.290 105.670 86.300 ;
        RECT 105.900 86.300 108.350 86.550 ;
        RECT 108.550 86.520 108.950 87.100 ;
        RECT 105.900 86.150 106.150 86.300 ;
        RECT 106.860 86.290 107.320 86.300 ;
        RECT 105.750 86.130 106.150 86.150 ;
        RECT 108.100 86.130 108.350 86.300 ;
        RECT 108.510 86.290 108.970 86.520 ;
        RECT 103.280 85.550 103.510 86.130 ;
        RECT 103.150 85.130 103.510 85.550 ;
        RECT 104.070 85.700 104.450 86.130 ;
        RECT 104.070 85.130 104.300 85.700 ;
        RECT 104.930 85.550 105.160 86.130 ;
        RECT 104.800 85.130 105.160 85.550 ;
        RECT 105.720 85.700 106.150 86.130 ;
        RECT 105.720 85.130 105.950 85.700 ;
        RECT 106.580 85.550 106.810 86.130 ;
        RECT 106.450 85.130 106.810 85.550 ;
        RECT 107.370 86.100 107.600 86.130 ;
        RECT 107.370 85.200 107.900 86.100 ;
        RECT 108.100 85.700 108.460 86.130 ;
        RECT 107.370 85.130 107.600 85.200 ;
        RECT 108.230 85.130 108.460 85.700 ;
        RECT 109.020 85.550 109.250 86.130 ;
        RECT 109.020 85.130 109.400 85.550 ;
        RECT 103.150 84.850 103.400 85.130 ;
        RECT 104.800 84.850 105.050 85.130 ;
        RECT 106.450 84.850 106.700 85.130 ;
        RECT 109.150 84.850 109.400 85.130 ;
        RECT 103.150 84.700 109.400 84.850 ;
        RECT 95.500 83.700 109.400 84.700 ;
        RECT 102.600 79.000 103.850 83.700 ;
        RECT 118.600 79.800 119.600 84.100 ;
        RECT 122.800 82.800 123.800 88.300 ;
        RECT 125.800 85.600 126.800 87.700 ;
        RECT 125.600 84.600 126.800 85.600 ;
        RECT 122.800 81.800 125.300 82.800 ;
        RECT 122.800 79.800 123.800 81.800 ;
        RECT 124.300 79.800 125.300 81.800 ;
        RECT 125.800 79.800 126.800 84.600 ;
        RECT 127.800 79.800 128.800 89.100 ;
        RECT 135.500 88.950 136.500 89.360 ;
        RECT 135.170 88.360 137.275 88.950 ;
        RECT 145.165 88.360 147.270 88.950 ;
        RECT 146.000 87.950 147.000 88.360 ;
        RECT 132.800 86.700 134.600 87.700 ;
        RECT 135.170 87.360 137.275 87.950 ;
        RECT 145.165 87.360 147.270 87.950 ;
        RECT 135.500 86.950 136.500 87.360 ;
        RECT 135.170 86.360 137.275 86.950 ;
        RECT 145.165 86.360 147.270 86.950 ;
        RECT 146.000 85.950 147.000 86.360 ;
        RECT 135.170 85.360 137.275 85.950 ;
        RECT 145.165 85.360 147.270 85.950 ;
        RECT 135.500 84.950 136.500 85.360 ;
        RECT 135.170 84.360 137.275 84.950 ;
        RECT 145.165 84.360 147.270 84.950 ;
        RECT 132.800 83.950 135.200 84.100 ;
        RECT 146.000 83.950 147.000 84.360 ;
        RECT 132.800 83.360 137.275 83.950 ;
        RECT 145.165 83.360 147.270 83.950 ;
        RECT 132.800 83.100 135.200 83.360 ;
        RECT 129.800 79.800 130.800 82.800 ;
        RECT 131.300 81.700 132.300 81.800 ;
        RECT 131.300 81.570 135.200 81.700 ;
        RECT 147.100 81.570 149.750 81.750 ;
        RECT 131.300 80.980 137.165 81.570 ;
        RECT 145.055 80.980 149.750 81.570 ;
        RECT 131.300 80.800 135.200 80.980 ;
        RECT 131.300 79.800 132.300 80.800 ;
        RECT 147.100 80.750 149.750 80.980 ;
        RECT 88.500 78.000 149.750 79.000 ;
        RECT 88.500 77.000 89.700 78.000 ;
        RECT 102.600 77.000 103.850 78.000 ;
        RECT 131.000 77.000 132.200 78.000 ;
        RECT 145.090 77.990 146.300 78.000 ;
        RECT 145.100 77.000 146.300 77.990 ;
        RECT 84.000 76.400 94.200 77.000 ;
        RECT 84.000 66.400 84.600 76.400 ;
        RECT 88.500 75.570 89.700 76.400 ;
        RECT 85.450 75.280 92.770 75.570 ;
        RECT 85.450 67.540 85.740 75.280 ;
        RECT 88.500 73.560 89.700 75.280 ;
        RECT 87.460 73.270 90.760 73.560 ;
        RECT 87.460 69.550 87.750 73.270 ;
        RECT 88.500 69.550 89.700 73.270 ;
        RECT 90.470 69.550 90.760 73.270 ;
        RECT 87.460 69.260 90.760 69.550 ;
        RECT 88.500 67.540 89.700 69.260 ;
        RECT 92.480 67.540 92.770 75.280 ;
        RECT 85.450 67.250 92.770 67.540 ;
        RECT 88.500 66.400 89.700 67.250 ;
        RECT 93.600 66.400 94.200 76.400 ;
        RECT 84.000 65.800 94.200 66.400 ;
        RECT 98.200 76.400 108.400 77.000 ;
        RECT 98.200 66.400 98.800 76.400 ;
        RECT 102.600 75.570 103.850 76.400 ;
        RECT 99.600 75.280 106.920 75.570 ;
        RECT 99.600 67.540 99.890 75.280 ;
        RECT 102.600 73.560 103.850 75.280 ;
        RECT 101.610 73.270 104.910 73.560 ;
        RECT 101.610 69.550 101.900 73.270 ;
        RECT 102.600 70.100 103.850 73.270 ;
        RECT 104.620 69.550 104.910 73.270 ;
        RECT 101.610 69.260 104.910 69.550 ;
        RECT 106.630 67.540 106.920 75.280 ;
        RECT 99.600 67.250 106.920 67.540 ;
        RECT 107.800 66.400 108.400 76.400 ;
        RECT 98.200 65.800 108.400 66.400 ;
        RECT 112.300 76.400 122.500 77.000 ;
        RECT 112.300 66.400 112.900 76.400 ;
        RECT 118.600 75.570 119.600 75.900 ;
        RECT 113.750 75.280 121.070 75.570 ;
        RECT 113.750 67.540 114.040 75.280 ;
        RECT 118.600 74.900 119.600 75.280 ;
        RECT 118.600 73.560 119.600 73.700 ;
        RECT 115.760 73.270 119.600 73.560 ;
        RECT 115.760 69.550 116.050 73.270 ;
        RECT 118.600 72.700 119.600 73.270 ;
        RECT 116.905 70.545 117.915 72.275 ;
        RECT 118.770 69.550 119.060 72.700 ;
        RECT 115.760 69.260 119.060 69.550 ;
        RECT 120.780 67.540 121.070 75.280 ;
        RECT 113.750 67.250 121.070 67.540 ;
        RECT 121.900 66.400 122.500 76.400 ;
        RECT 112.300 65.800 122.500 66.400 ;
        RECT 126.500 76.400 136.700 77.000 ;
        RECT 126.500 66.400 127.100 76.400 ;
        RECT 131.000 75.570 132.200 76.400 ;
        RECT 127.900 75.280 135.220 75.570 ;
        RECT 127.900 67.540 128.190 75.280 ;
        RECT 131.000 73.560 132.200 75.280 ;
        RECT 129.910 73.270 133.210 73.560 ;
        RECT 129.910 69.550 130.200 73.270 ;
        RECT 131.000 70.100 132.200 73.270 ;
        RECT 132.920 69.550 133.210 73.270 ;
        RECT 129.910 69.260 133.210 69.550 ;
        RECT 134.930 67.540 135.220 75.280 ;
        RECT 127.900 67.250 135.220 67.540 ;
        RECT 136.100 66.400 136.700 76.400 ;
        RECT 126.500 65.800 136.700 66.400 ;
        RECT 140.600 76.400 150.800 77.000 ;
        RECT 140.600 66.400 141.200 76.400 ;
        RECT 145.100 75.570 146.300 76.400 ;
        RECT 142.050 75.280 149.370 75.570 ;
        RECT 142.050 67.540 142.340 75.280 ;
        RECT 145.100 73.560 146.300 75.280 ;
        RECT 144.060 73.270 147.360 73.560 ;
        RECT 144.060 69.550 144.350 73.270 ;
        RECT 145.100 69.550 146.300 73.270 ;
        RECT 147.070 69.550 147.360 73.270 ;
        RECT 144.060 69.260 147.360 69.550 ;
        RECT 145.100 67.540 146.300 69.260 ;
        RECT 149.080 67.540 149.370 75.280 ;
        RECT 142.050 67.250 149.370 67.540 ;
        RECT 145.100 66.400 146.300 67.250 ;
        RECT 150.200 66.400 150.800 76.400 ;
        RECT 140.600 65.800 150.800 66.400 ;
        RECT 88.500 61.900 89.700 65.800 ;
        RECT 145.100 61.900 146.300 65.800 ;
        RECT 84.000 61.300 136.700 61.900 ;
        RECT 84.000 51.300 84.600 61.300 ;
        RECT 88.500 60.420 89.700 61.300 ;
        RECT 85.450 60.130 92.770 60.420 ;
        RECT 85.450 52.390 85.740 60.130 ;
        RECT 88.500 58.410 89.700 60.130 ;
        RECT 87.460 58.120 90.760 58.410 ;
        RECT 87.460 54.400 87.750 58.120 ;
        RECT 88.500 54.400 89.700 58.120 ;
        RECT 90.470 54.400 90.760 58.120 ;
        RECT 87.460 54.110 90.760 54.400 ;
        RECT 88.500 52.390 89.700 54.110 ;
        RECT 92.480 52.390 92.770 60.130 ;
        RECT 85.450 52.100 92.770 52.390 ;
        RECT 88.500 51.300 89.700 52.100 ;
        RECT 93.600 51.300 94.200 61.300 ;
        RECT 84.000 50.700 94.200 51.300 ;
        RECT 98.200 51.300 98.800 61.300 ;
        RECT 99.600 60.130 106.920 60.420 ;
        RECT 99.600 52.390 99.890 60.130 ;
        RECT 101.610 58.120 104.910 58.410 ;
        RECT 101.610 54.400 101.900 58.120 ;
        RECT 102.755 57.000 103.765 57.125 ;
        RECT 102.755 56.000 103.800 57.000 ;
        RECT 102.755 55.395 103.765 56.000 ;
        RECT 104.620 55.000 104.910 58.120 ;
        RECT 104.300 54.400 105.300 55.000 ;
        RECT 101.610 54.110 105.300 54.400 ;
        RECT 104.300 54.000 105.300 54.110 ;
        RECT 106.630 53.000 106.920 60.130 ;
        RECT 106.300 52.390 107.300 53.000 ;
        RECT 99.600 52.100 107.300 52.390 ;
        RECT 106.300 52.000 107.300 52.100 ;
        RECT 107.800 51.300 108.400 61.300 ;
        RECT 98.200 50.700 108.400 51.300 ;
        RECT 112.300 51.300 112.900 61.300 ;
        RECT 113.750 60.130 121.070 60.420 ;
        RECT 113.750 53.000 114.040 60.130 ;
        RECT 115.760 58.120 119.060 58.410 ;
        RECT 115.760 55.000 116.050 58.120 ;
        RECT 116.905 57.000 117.915 57.125 ;
        RECT 116.800 56.000 117.915 57.000 ;
        RECT 116.905 55.395 117.915 56.000 ;
        RECT 115.300 54.400 116.300 55.000 ;
        RECT 118.770 54.400 119.060 58.120 ;
        RECT 115.300 54.110 119.060 54.400 ;
        RECT 115.300 54.000 116.300 54.110 ;
        RECT 113.750 52.390 114.800 53.000 ;
        RECT 120.780 52.390 121.070 60.130 ;
        RECT 113.750 52.100 121.070 52.390 ;
        RECT 113.800 52.000 114.800 52.100 ;
        RECT 121.900 51.300 122.500 61.300 ;
        RECT 112.300 50.700 122.500 51.300 ;
        RECT 126.500 51.300 127.100 61.300 ;
        RECT 127.900 60.130 135.220 60.420 ;
        RECT 127.900 53.000 128.190 60.130 ;
        RECT 129.910 58.120 133.210 58.410 ;
        RECT 129.910 55.000 130.200 58.120 ;
        RECT 131.055 57.000 132.065 57.125 ;
        RECT 131.055 56.000 132.300 57.000 ;
        RECT 131.055 55.395 132.065 56.000 ;
        RECT 129.800 54.400 130.800 55.000 ;
        RECT 132.920 54.400 133.210 58.120 ;
        RECT 129.800 54.110 133.210 54.400 ;
        RECT 129.800 54.000 130.800 54.110 ;
        RECT 127.800 52.390 128.800 53.000 ;
        RECT 134.930 52.390 135.220 60.130 ;
        RECT 127.800 52.100 135.220 52.390 ;
        RECT 127.800 52.000 128.800 52.100 ;
        RECT 136.100 51.300 136.700 61.300 ;
        RECT 126.500 50.700 136.700 51.300 ;
        RECT 140.600 61.300 150.800 61.900 ;
        RECT 140.600 51.300 141.200 61.300 ;
        RECT 145.100 60.420 146.300 61.300 ;
        RECT 142.050 60.130 149.370 60.420 ;
        RECT 142.050 52.390 142.340 60.130 ;
        RECT 145.100 58.410 146.300 60.130 ;
        RECT 144.060 58.120 147.360 58.410 ;
        RECT 144.060 54.400 144.350 58.120 ;
        RECT 145.100 54.400 146.300 58.120 ;
        RECT 147.070 54.400 147.360 58.120 ;
        RECT 144.060 54.110 147.360 54.400 ;
        RECT 145.100 52.390 146.300 54.110 ;
        RECT 149.080 52.390 149.370 60.130 ;
        RECT 142.050 52.100 149.370 52.390 ;
        RECT 145.100 51.300 146.300 52.100 ;
        RECT 150.200 51.300 150.800 61.300 ;
        RECT 140.600 50.700 150.800 51.300 ;
        RECT 88.500 46.700 89.700 50.700 ;
        RECT 145.100 46.700 146.300 50.700 ;
        RECT 84.000 46.100 136.700 46.700 ;
        RECT 84.000 36.100 84.600 46.100 ;
        RECT 88.500 45.270 89.700 46.100 ;
        RECT 85.450 44.980 92.770 45.270 ;
        RECT 85.450 37.240 85.740 44.980 ;
        RECT 88.500 43.260 89.700 44.980 ;
        RECT 87.460 42.970 90.760 43.260 ;
        RECT 87.460 39.250 87.750 42.970 ;
        RECT 88.500 39.250 89.700 42.970 ;
        RECT 90.470 39.250 90.760 42.970 ;
        RECT 87.460 38.960 90.760 39.250 ;
        RECT 88.500 37.240 89.700 38.960 ;
        RECT 92.480 37.240 92.770 44.980 ;
        RECT 85.450 36.950 92.770 37.240 ;
        RECT 88.500 36.100 89.700 36.950 ;
        RECT 93.600 36.100 94.200 46.100 ;
        RECT 84.000 35.500 94.200 36.100 ;
        RECT 98.200 36.100 98.800 46.100 ;
        RECT 99.600 44.980 106.920 45.270 ;
        RECT 99.600 37.240 99.890 44.980 ;
        RECT 101.610 42.970 104.910 43.260 ;
        RECT 101.610 39.250 101.900 42.970 ;
        RECT 102.755 41.600 103.765 41.975 ;
        RECT 104.620 41.600 104.910 42.970 ;
        RECT 106.630 41.600 106.920 44.980 ;
        RECT 102.755 40.600 103.800 41.600 ;
        RECT 104.300 40.600 105.300 41.600 ;
        RECT 106.300 40.600 107.300 41.600 ;
        RECT 102.755 40.245 103.765 40.600 ;
        RECT 104.620 39.250 104.910 40.600 ;
        RECT 101.610 38.960 104.910 39.250 ;
        RECT 106.630 37.240 106.920 40.600 ;
        RECT 99.600 36.950 106.920 37.240 ;
        RECT 107.800 36.100 108.400 46.100 ;
        RECT 98.200 35.500 108.400 36.100 ;
        RECT 112.300 36.100 112.900 46.100 ;
        RECT 116.900 45.270 117.900 45.800 ;
        RECT 113.750 44.980 121.070 45.270 ;
        RECT 113.750 37.240 114.040 44.980 ;
        RECT 116.900 44.800 117.900 44.980 ;
        RECT 116.900 43.260 117.900 43.800 ;
        RECT 115.760 42.970 119.060 43.260 ;
        RECT 115.760 39.250 116.050 42.970 ;
        RECT 116.900 42.800 117.900 42.970 ;
        RECT 116.905 40.245 117.915 41.975 ;
        RECT 118.770 39.250 119.060 42.970 ;
        RECT 115.760 38.960 119.060 39.250 ;
        RECT 120.780 37.240 121.070 44.980 ;
        RECT 113.750 36.950 121.070 37.240 ;
        RECT 121.900 36.100 122.500 46.100 ;
        RECT 112.300 35.500 122.500 36.100 ;
        RECT 126.500 36.100 127.100 46.100 ;
        RECT 127.900 44.980 135.220 45.270 ;
        RECT 127.900 41.500 128.190 44.980 ;
        RECT 129.910 42.970 133.210 43.260 ;
        RECT 129.910 41.500 130.200 42.970 ;
        RECT 131.055 41.500 132.065 41.975 ;
        RECT 127.800 40.500 128.800 41.500 ;
        RECT 129.800 40.500 130.800 41.500 ;
        RECT 131.055 40.500 132.300 41.500 ;
        RECT 127.900 37.240 128.190 40.500 ;
        RECT 129.910 39.250 130.200 40.500 ;
        RECT 131.055 40.245 132.065 40.500 ;
        RECT 132.920 39.250 133.210 42.970 ;
        RECT 129.910 38.960 133.210 39.250 ;
        RECT 134.930 37.240 135.220 44.980 ;
        RECT 127.900 36.950 135.220 37.240 ;
        RECT 136.100 36.100 136.700 46.100 ;
        RECT 126.500 35.500 136.700 36.100 ;
        RECT 140.600 46.100 150.800 46.700 ;
        RECT 140.600 36.100 141.200 46.100 ;
        RECT 145.100 45.270 146.300 46.100 ;
        RECT 142.050 44.980 149.370 45.270 ;
        RECT 142.050 37.240 142.340 44.980 ;
        RECT 145.100 43.260 146.300 44.980 ;
        RECT 144.060 42.970 147.360 43.260 ;
        RECT 144.060 39.250 144.350 42.970 ;
        RECT 145.100 39.250 146.300 42.970 ;
        RECT 147.070 39.250 147.360 42.970 ;
        RECT 144.060 38.960 147.360 39.250 ;
        RECT 145.100 37.240 146.300 38.960 ;
        RECT 149.080 37.240 149.370 44.980 ;
        RECT 142.050 36.950 149.370 37.240 ;
        RECT 145.100 36.100 146.300 36.950 ;
        RECT 150.200 36.100 150.800 46.100 ;
        RECT 140.600 35.500 150.800 36.100 ;
        RECT 88.500 31.600 89.700 35.500 ;
        RECT 145.100 31.600 146.300 35.500 ;
        RECT 84.000 31.000 136.700 31.600 ;
        RECT 84.000 21.000 84.600 31.000 ;
        RECT 88.500 30.120 89.700 31.000 ;
        RECT 85.450 29.830 92.770 30.120 ;
        RECT 85.450 22.090 85.740 29.830 ;
        RECT 88.500 28.110 89.700 29.830 ;
        RECT 87.460 27.820 90.760 28.110 ;
        RECT 87.460 24.100 87.750 27.820 ;
        RECT 88.500 24.100 89.700 27.820 ;
        RECT 90.470 24.100 90.760 27.820 ;
        RECT 87.460 23.810 90.760 24.100 ;
        RECT 88.500 22.090 89.700 23.810 ;
        RECT 92.480 22.090 92.770 29.830 ;
        RECT 85.450 21.800 92.770 22.090 ;
        RECT 88.500 21.000 89.700 21.800 ;
        RECT 93.600 21.000 94.200 31.000 ;
        RECT 84.000 20.400 94.200 21.000 ;
        RECT 98.200 21.000 98.800 31.000 ;
        RECT 106.300 30.120 107.300 30.500 ;
        RECT 99.600 29.830 107.300 30.120 ;
        RECT 99.600 22.090 99.890 29.830 ;
        RECT 106.300 29.500 107.300 29.830 ;
        RECT 104.300 28.110 105.300 28.500 ;
        RECT 101.610 27.820 105.300 28.110 ;
        RECT 101.610 24.100 101.900 27.820 ;
        RECT 104.300 27.500 105.300 27.820 ;
        RECT 102.755 26.500 103.765 26.825 ;
        RECT 102.755 25.500 103.800 26.500 ;
        RECT 102.755 25.095 103.765 25.500 ;
        RECT 104.620 24.100 104.910 27.500 ;
        RECT 101.610 23.810 104.910 24.100 ;
        RECT 106.630 22.090 106.920 29.500 ;
        RECT 99.600 21.800 106.920 22.090 ;
        RECT 107.800 21.000 108.400 31.000 ;
        RECT 98.200 20.400 108.400 21.000 ;
        RECT 112.300 21.000 112.900 31.000 ;
        RECT 117.000 30.120 118.000 30.500 ;
        RECT 113.750 29.830 121.070 30.120 ;
        RECT 113.750 22.090 114.040 29.830 ;
        RECT 117.000 29.500 118.000 29.830 ;
        RECT 116.900 28.110 117.900 28.500 ;
        RECT 115.760 27.820 119.060 28.110 ;
        RECT 115.760 24.100 116.050 27.820 ;
        RECT 116.900 27.500 117.900 27.820 ;
        RECT 116.905 26.500 117.915 26.825 ;
        RECT 116.900 25.500 117.915 26.500 ;
        RECT 116.905 25.095 117.915 25.500 ;
        RECT 118.770 24.100 119.060 27.820 ;
        RECT 115.760 23.810 119.060 24.100 ;
        RECT 120.780 22.090 121.070 29.830 ;
        RECT 113.750 21.800 121.070 22.090 ;
        RECT 121.900 21.000 122.500 31.000 ;
        RECT 112.300 20.400 122.500 21.000 ;
        RECT 126.500 21.000 127.100 31.000 ;
        RECT 127.800 30.120 128.800 30.500 ;
        RECT 127.800 29.830 135.220 30.120 ;
        RECT 127.800 29.500 128.800 29.830 ;
        RECT 127.900 22.090 128.190 29.500 ;
        RECT 129.800 28.110 130.800 28.500 ;
        RECT 129.800 27.820 133.210 28.110 ;
        RECT 129.800 27.500 130.800 27.820 ;
        RECT 129.910 24.100 130.200 27.500 ;
        RECT 131.055 26.500 132.065 26.825 ;
        RECT 131.055 25.500 132.300 26.500 ;
        RECT 131.055 25.095 132.065 25.500 ;
        RECT 132.920 24.100 133.210 27.820 ;
        RECT 129.910 23.810 133.210 24.100 ;
        RECT 134.930 22.090 135.220 29.830 ;
        RECT 127.900 21.800 135.220 22.090 ;
        RECT 136.100 21.000 136.700 31.000 ;
        RECT 126.500 20.400 136.700 21.000 ;
        RECT 140.600 31.000 150.800 31.600 ;
        RECT 140.600 21.000 141.200 31.000 ;
        RECT 145.100 30.120 146.300 31.000 ;
        RECT 142.050 29.830 149.370 30.120 ;
        RECT 142.050 22.090 142.340 29.830 ;
        RECT 145.100 28.110 146.300 29.830 ;
        RECT 144.060 27.820 147.360 28.110 ;
        RECT 144.060 24.100 144.350 27.820 ;
        RECT 145.100 24.100 146.300 27.820 ;
        RECT 147.070 24.100 147.360 27.820 ;
        RECT 144.060 23.810 147.360 24.100 ;
        RECT 145.100 22.090 146.300 23.810 ;
        RECT 149.080 22.090 149.370 29.830 ;
        RECT 142.050 21.800 149.370 22.090 ;
        RECT 145.100 21.000 146.300 21.800 ;
        RECT 150.200 21.000 150.800 31.000 ;
        RECT 140.600 20.400 150.800 21.000 ;
        RECT 88.500 16.400 89.700 20.400 ;
        RECT 145.100 16.400 146.300 20.400 ;
        RECT 84.000 15.800 94.200 16.400 ;
        RECT 84.000 5.800 84.600 15.800 ;
        RECT 88.500 14.970 89.700 15.800 ;
        RECT 85.450 14.680 92.770 14.970 ;
        RECT 85.450 6.940 85.740 14.680 ;
        RECT 88.500 12.960 89.700 14.680 ;
        RECT 87.460 12.670 90.760 12.960 ;
        RECT 87.460 8.950 87.750 12.670 ;
        RECT 88.500 8.950 89.700 12.670 ;
        RECT 90.470 8.950 90.760 12.670 ;
        RECT 87.460 8.660 90.760 8.950 ;
        RECT 88.500 6.940 89.700 8.660 ;
        RECT 92.480 6.940 92.770 14.680 ;
        RECT 85.450 6.650 92.770 6.940 ;
        RECT 88.500 5.800 89.700 6.650 ;
        RECT 93.600 5.800 94.200 15.800 ;
        RECT 84.000 5.200 94.200 5.800 ;
        RECT 98.200 15.800 108.400 16.400 ;
        RECT 98.200 5.800 98.800 15.800 ;
        RECT 99.600 14.680 106.920 14.970 ;
        RECT 99.600 6.940 99.890 14.680 ;
        RECT 101.610 12.670 104.910 12.960 ;
        RECT 101.610 8.950 101.900 12.670 ;
        RECT 102.700 8.950 103.900 11.900 ;
        RECT 104.620 8.950 104.910 12.670 ;
        RECT 101.610 8.660 104.910 8.950 ;
        RECT 102.700 6.940 103.900 8.660 ;
        RECT 106.630 6.940 106.920 14.680 ;
        RECT 99.600 6.650 106.920 6.940 ;
        RECT 102.700 5.800 103.900 6.650 ;
        RECT 107.800 5.800 108.400 15.800 ;
        RECT 98.200 5.200 108.400 5.800 ;
        RECT 112.300 15.800 122.500 16.400 ;
        RECT 112.300 5.800 112.900 15.800 ;
        RECT 113.750 14.680 121.070 14.970 ;
        RECT 113.750 6.940 114.040 14.680 ;
        RECT 115.760 12.670 119.060 12.960 ;
        RECT 115.760 8.950 116.050 12.670 ;
        RECT 116.800 8.950 118.000 11.900 ;
        RECT 118.770 8.950 119.060 12.670 ;
        RECT 115.760 8.660 119.060 8.950 ;
        RECT 116.800 6.940 118.000 8.660 ;
        RECT 120.780 6.940 121.070 14.680 ;
        RECT 113.750 6.650 121.070 6.940 ;
        RECT 116.800 5.800 118.000 6.650 ;
        RECT 121.900 5.800 122.500 15.800 ;
        RECT 112.300 5.200 122.500 5.800 ;
        RECT 126.500 15.800 136.700 16.400 ;
        RECT 126.500 5.800 127.100 15.800 ;
        RECT 127.900 14.680 135.220 14.970 ;
        RECT 127.900 6.940 128.190 14.680 ;
        RECT 129.910 12.670 133.210 12.960 ;
        RECT 129.910 8.950 130.200 12.670 ;
        RECT 130.900 8.950 132.100 11.900 ;
        RECT 132.920 8.950 133.210 12.670 ;
        RECT 129.910 8.660 133.210 8.950 ;
        RECT 130.900 6.940 132.100 8.660 ;
        RECT 134.930 6.940 135.220 14.680 ;
        RECT 127.900 6.650 135.220 6.940 ;
        RECT 130.900 5.800 132.100 6.650 ;
        RECT 136.100 5.800 136.700 15.800 ;
        RECT 126.500 5.200 136.700 5.800 ;
        RECT 140.600 15.800 150.800 16.400 ;
        RECT 140.600 5.800 141.200 15.800 ;
        RECT 145.100 14.970 146.300 15.800 ;
        RECT 142.050 14.680 149.370 14.970 ;
        RECT 142.050 6.940 142.340 14.680 ;
        RECT 145.100 12.960 146.300 14.680 ;
        RECT 144.060 12.670 147.360 12.960 ;
        RECT 144.060 8.950 144.350 12.670 ;
        RECT 145.100 8.950 146.300 12.670 ;
        RECT 147.070 8.950 147.360 12.670 ;
        RECT 144.060 8.660 147.360 8.950 ;
        RECT 145.100 6.940 146.300 8.660 ;
        RECT 149.080 6.940 149.370 14.680 ;
        RECT 142.050 6.650 149.370 6.940 ;
        RECT 145.100 5.800 146.300 6.650 ;
        RECT 150.200 5.800 150.800 15.800 ;
        RECT 140.600 5.200 150.800 5.800 ;
        RECT 88.500 3.000 89.700 5.200 ;
        RECT 102.700 4.000 103.900 5.200 ;
        RECT 116.800 4.000 118.000 5.200 ;
        RECT 130.900 4.000 132.100 5.200 ;
        RECT 145.100 4.000 146.300 5.200 ;
        RECT 102.700 3.000 146.300 4.000 ;
      LAYER met2 ;
        RECT 146.500 102.350 146.950 225.760 ;
        RECT 102.400 100.100 103.900 101.600 ;
        RECT 151.000 92.600 152.000 93.600 ;
        RECT 132.800 90.300 133.800 91.300 ;
        RECT 107.350 88.850 116.950 89.400 ;
        RECT 107.350 85.200 107.900 88.850 ;
        RECT 121.000 88.300 121.400 90.200 ;
        RECT 132.800 88.550 133.200 90.300 ;
        RECT 123.950 88.150 133.200 88.550 ;
        RECT 123.950 87.900 124.350 88.150 ;
        RECT 108.550 87.500 124.350 87.900 ;
        RECT 108.550 86.600 108.950 87.500 ;
        RECT 125.800 86.700 149.750 87.700 ;
        RECT 111.200 85.700 126.800 86.700 ;
        RECT 111.200 84.700 112.200 85.700 ;
        RECT 95.500 83.700 112.200 84.700 ;
        RECT 95.500 78.000 96.800 79.000 ;
        RECT 116.900 71.000 117.900 85.700 ;
        RECT 118.600 83.100 133.800 84.100 ;
        RECT 124.300 81.800 130.800 82.800 ;
        RECT 118.600 72.700 119.600 80.800 ;
        RECT 102.800 56.000 117.800 57.000 ;
        RECT 102.800 26.500 103.800 56.000 ;
        RECT 104.300 54.000 116.300 55.000 ;
        RECT 104.300 28.500 105.300 54.000 ;
        RECT 106.300 52.000 114.800 53.000 ;
        RECT 106.300 30.500 107.300 52.000 ;
        RECT 122.800 45.800 123.800 80.800 ;
        RECT 116.900 44.800 123.800 45.800 ;
        RECT 124.300 43.800 125.300 80.800 ;
        RECT 116.900 42.800 125.300 43.800 ;
        RECT 125.800 41.600 126.800 80.800 ;
        RECT 116.900 40.600 126.800 41.600 ;
        RECT 127.800 30.500 128.800 80.800 ;
        RECT 106.300 29.500 128.800 30.500 ;
        RECT 129.800 28.500 130.800 80.800 ;
        RECT 104.300 27.500 130.800 28.500 ;
        RECT 131.300 26.500 132.300 80.800 ;
        RECT 148.750 80.750 149.750 86.700 ;
        RECT 134.400 78.000 148.600 79.000 ;
        RECT 102.800 25.500 132.300 26.500 ;
      LAYER met3 ;
        RECT 146.500 224.750 146.950 225.760 ;
        RECT 1.000 100.100 9.000 101.600 ;
        RECT 102.400 100.100 103.900 101.600 ;
        RECT 95.500 83.700 96.800 84.700 ;
        RECT 134.950 79.500 149.350 102.360 ;
        RECT 151.000 92.600 152.000 93.600 ;
        RECT 95.500 78.000 96.800 79.000 ;
        RECT 134.400 78.000 148.600 79.000 ;
      LAYER met4 ;
        RECT 5.000 224.760 30.670 225.000 ;
        RECT 30.970 224.760 33.430 225.000 ;
        RECT 33.730 224.760 36.190 225.000 ;
        RECT 36.490 224.760 38.950 225.000 ;
        RECT 39.250 224.760 41.710 225.000 ;
        RECT 42.010 224.760 44.470 225.000 ;
        RECT 44.770 224.760 47.230 225.000 ;
        RECT 47.530 224.760 49.990 225.000 ;
        RECT 50.290 224.760 52.750 225.000 ;
        RECT 53.050 224.760 55.510 225.000 ;
        RECT 55.810 224.760 58.270 225.000 ;
        RECT 58.570 224.760 61.030 225.000 ;
        RECT 61.330 224.760 63.790 225.000 ;
        RECT 64.090 224.760 66.550 225.000 ;
        RECT 66.850 224.760 69.310 225.000 ;
        RECT 69.610 224.760 72.070 225.000 ;
        RECT 72.370 224.760 74.830 225.000 ;
        RECT 75.130 224.760 77.590 225.000 ;
        RECT 77.890 224.760 80.350 225.000 ;
        RECT 80.650 224.760 83.110 225.000 ;
        RECT 83.410 224.760 85.870 225.000 ;
        RECT 86.170 224.760 88.630 225.000 ;
        RECT 88.930 224.760 91.390 225.000 ;
        RECT 91.690 224.760 94.150 225.000 ;
        RECT 94.450 224.760 94.500 225.000 ;
        RECT 5.000 224.500 94.500 224.760 ;
        RECT 146.500 224.760 146.590 225.760 ;
        RECT 146.890 224.760 146.950 225.760 ;
        RECT 146.500 224.750 146.950 224.760 ;
        RECT 5.000 220.760 5.500 224.500 ;
        RECT 7.500 100.100 103.900 101.600 ;
        RECT 6.000 97.700 96.800 99.200 ;
        RECT 95.500 78.000 96.800 97.700 ;
        RECT 135.345 93.600 148.955 101.965 ;
        RECT 135.345 92.600 152.800 93.600 ;
        RECT 135.345 81.355 148.955 92.600 ;
        RECT 134.400 78.000 149.350 80.000 ;
        RECT 151.800 1.000 152.800 92.600 ;
        RECT 151.800 0.000 151.810 1.000 ;
        RECT 152.710 0.000 152.800 1.000 ;
  END
END tt_ik_0_ptat_bgr
END LIBRARY

